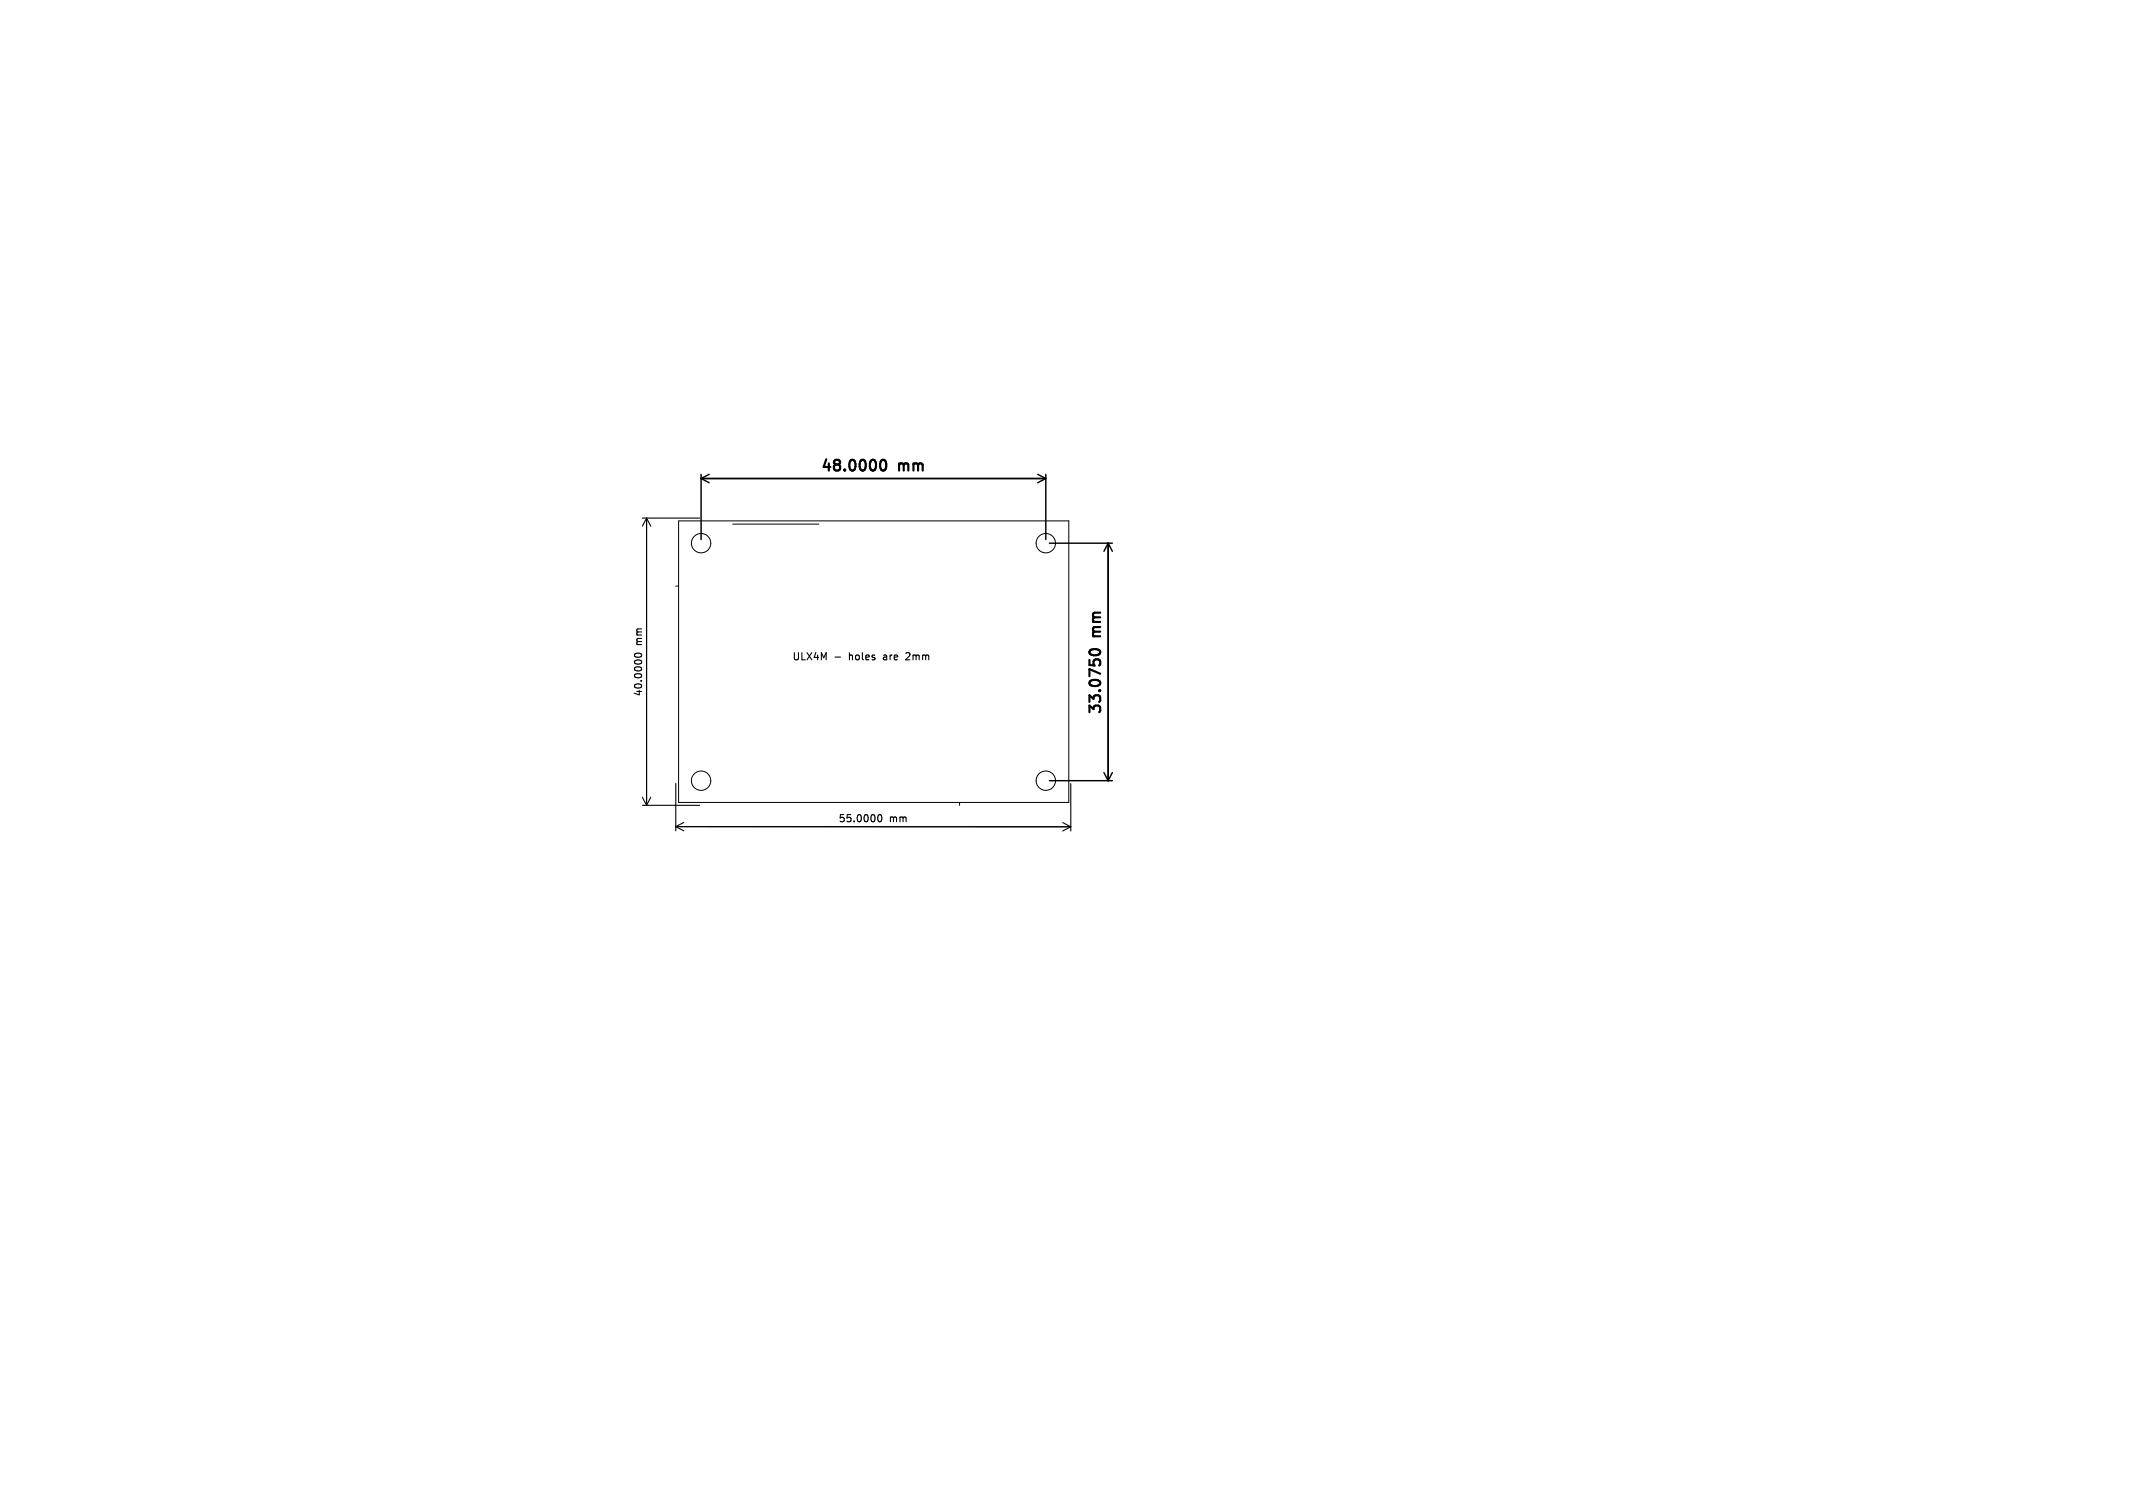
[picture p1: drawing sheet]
<svg xmlns="http://www.w3.org/2000/svg" width="297mm" height="210mm" viewBox="0 0 297 210" stroke-linecap="round" stroke-linejoin="round" font-family="sans-serif">
<defs><g id="words">
<g font-size="2.1">
<text x="114.2" y="66">48.0000</text>
<text x="125.1" y="66">mm</text>
<text x="153.6" y="88.7" transform="rotate(-90 153.6 88.7)">mm</text>
<text x="153.6" y="99.6" transform="rotate(-90 153.6 99.6)">33.0750</text>
</g>
<g font-size="1.4">
<text x="89.6" y="89.9" transform="rotate(-90 89.6 89.9)">mm</text>
<text x="110.4" y="92">ULX4M</text>
<text x="116.2" y="92">-</text>
<text x="118.4" y="92">holes</text>
<text x="123.3" y="92">are</text>
<text x="126.6" y="92">2mm</text>
<text x="89.6" y="97" transform="rotate(-90 89.6 97)">40.0000</text>
<text x="116.7" y="114.7">55.0000</text>
<text x="123.8" y="114.7">mm</text>
</g>
</g></defs>
<g fill="none" stroke="#000" stroke-width=".15">
<path d="M89.4 72.1h8M90 72.1v40M90 72.1l.6 1.2M90 72.1l-.6 1.2M88.4 91.1a.59 .59 0 0 1 .9 .2 .57 .57 0 0 1-1-.1zM126.3 90.9l-.2 .1M126.7 91.3l-.6 .6h.6M89.4 112.1h8M89.4 111l.6 1.1M90.6 111l-.6 1.1M94.1 115.1h55M94.1 115.1l1.1 .6"/>
<path d="M94.1 109.1v6.6M95.2 114.5l-1.1 .6M122.3 113.5l.2-.1a.53 .53 0 0 1 .3 .5 .53 .53 0 0 1-.3 .5l-.2-.1-.1-.2zM148 114.6l1.1 .5M149.1 115.1l-1.1 .6M149.1 109.1v6.6"/>
</g>
<path d="M122.8 64.1a.36 .36 0 0 1 .5 .2 .77 .77 0 0 1-.4 1.2 1 1 0 0 1-.1-1.4zM151.8 90.5a1.02 1.02 0 0 1 1.4 .3v.1a.94 .94 0 0 1-1.5 0z" fill="none" stroke="#000" stroke-width=".3"/>
<g fill="none" stroke="#000" stroke-width=".2">
<path d="M97.6 66.1v9M97.6 66.6h48M97.6 66.6l1.1 .6M98.7 66.1l-1.1 .5M144.5 66.1l1.1 .5M145.6 66.1v9M145.6 66.6l-1.1 .6M146.1 75.6h8.8M154.3 75.6v33.1M154.3 75.6l.6 1.2M154.3 75.6l-.6 1.2M146.1 108.7h8.8"/>
<path d="M153.7 107.6l.6 1.1M154.9 107.6l-.6 1.1"/>
</g>
<g fill="none" stroke="#000" stroke-width=".14">
<path d="M102 73h12M94.1 81.6h.4M133.6 111.8v.3M148.8 111.8h-54.3v-39.3h54.3v39.3"/>
<circle cx="97.6" cy="75.6" r="1.35"/>
<circle cx="145.6" cy="75.6" r="1.35"/>
<circle cx="97.6" cy="108.7" r="1.35"/>
<circle cx="145.6" cy="108.7" r="1.35"/>
</g>
<use href="#words"/>
</svg>
